VERSION 5.7 ;
  NOWIREEXTENSIONATPIN ON ;
  DIVIDERCHAR "/" ;
  BUSBITCHARS "[]" ;
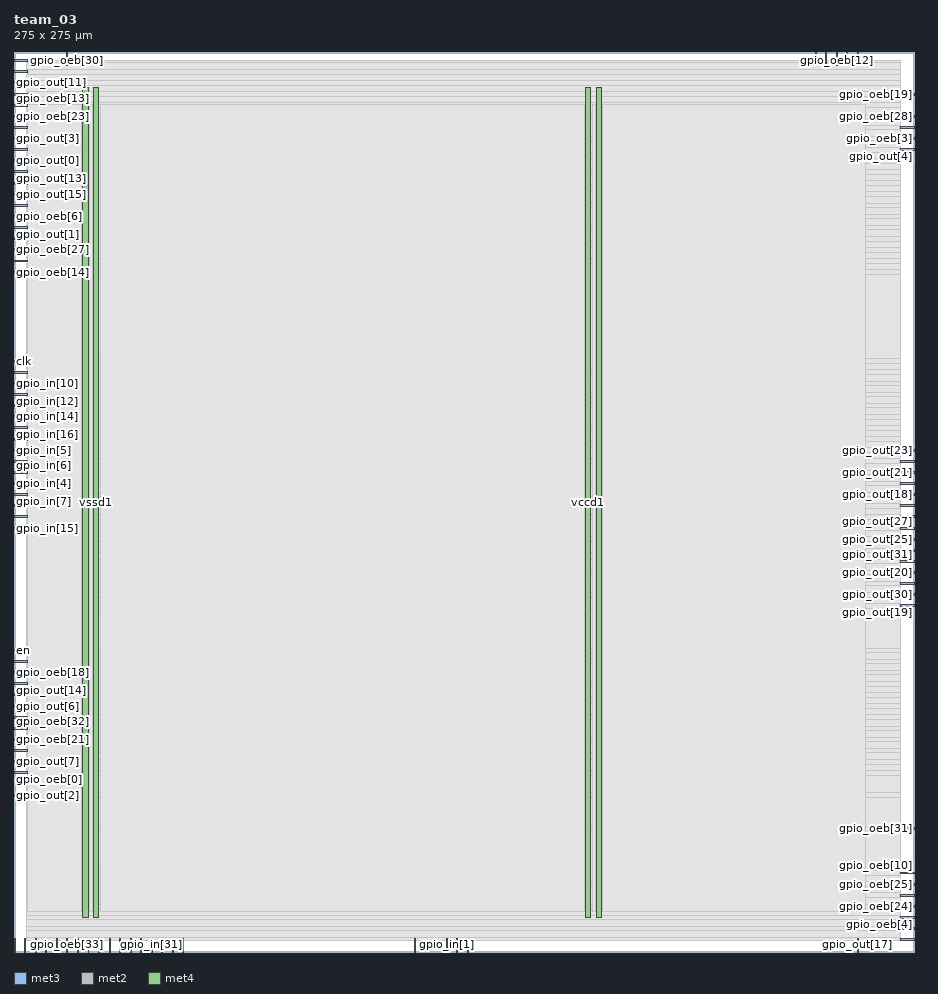
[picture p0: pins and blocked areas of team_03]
MACRO team_03
  CLASS BLOCK ;
  FOREIGN team_03 ;
  ORIGIN 0.000 0.000 ;
  SIZE 275.000 BY 275.000 ;
  PIN clk
    DIRECTION INPUT ;
    USE SIGNAL ;
    ANTENNAGATEAREA 1.286700 ;
    ANTENNADIFFAREA 0.434700 ;
    PORT
      LAYER met3 ;
        RECT 0.000 180.240 4.000 180.840 ;
    END
  END clk
  PIN en
    DIRECTION INPUT ;
    USE SIGNAL ;
    ANTENNAGATEAREA 0.631200 ;
    ANTENNADIFFAREA 0.434700 ;
    PORT
      LAYER met3 ;
        RECT 0.000 91.840 4.000 92.440 ;
    END
  END en
  PIN gpio_in[0]
    DIRECTION INPUT ;
    USE SIGNAL ;
    ANTENNAGATEAREA 0.631200 ;
    ANTENNADIFFAREA 0.434700 ;
    PORT
      LAYER met2 ;
        RECT 135.330 0.000 135.610 4.000 ;
    END
  END gpio_in[0]
  PIN gpio_in[10]
    DIRECTION INPUT ;
    USE SIGNAL ;
    ANTENNAGATEAREA 0.647700 ;
    ANTENNADIFFAREA 0.434700 ;
    PORT
      LAYER met3 ;
        RECT 0.000 173.440 4.000 174.040 ;
    END
  END gpio_in[10]
  PIN gpio_in[11]
    DIRECTION INPUT ;
    USE SIGNAL ;
    ANTENNAGATEAREA 0.593700 ;
    ANTENNADIFFAREA 0.434700 ;
    PORT
      LAYER met3 ;
        RECT 0.000 176.840 4.000 177.440 ;
    END
  END gpio_in[11]
  PIN gpio_in[12]
    DIRECTION INPUT ;
    USE SIGNAL ;
    ANTENNAGATEAREA 0.647700 ;
    ANTENNADIFFAREA 0.434700 ;
    PORT
      LAYER met3 ;
        RECT 0.000 170.040 4.000 170.640 ;
    END
  END gpio_in[12]
  PIN gpio_in[13]
    DIRECTION INPUT ;
    USE SIGNAL ;
    ANTENNAGATEAREA 0.593700 ;
    ANTENNADIFFAREA 0.434700 ;
    PORT
      LAYER met3 ;
        RECT 0.000 166.640 4.000 167.240 ;
    END
  END gpio_in[13]
  PIN gpio_in[14]
    DIRECTION INPUT ;
    USE SIGNAL ;
    ANTENNAGATEAREA 0.647700 ;
    ANTENNADIFFAREA 0.434700 ;
    PORT
      LAYER met3 ;
        RECT 0.000 163.240 4.000 163.840 ;
    END
  END gpio_in[14]
  PIN gpio_in[15]
    DIRECTION INPUT ;
    USE SIGNAL ;
    ANTENNAGATEAREA 0.593700 ;
    ANTENNADIFFAREA 0.434700 ;
    PORT
      LAYER met3 ;
        RECT 0.000 129.240 4.000 129.840 ;
    END
  END gpio_in[15]
  PIN gpio_in[16]
    DIRECTION INPUT ;
    USE SIGNAL ;
    ANTENNAGATEAREA 0.593700 ;
    ANTENNADIFFAREA 0.434700 ;
    PORT
      LAYER met3 ;
        RECT 0.000 159.840 4.000 160.440 ;
    END
  END gpio_in[16]
  PIN gpio_in[17]
    DIRECTION INPUT ;
    USE SIGNAL ;
    ANTENNAGATEAREA 0.593700 ;
    ANTENNADIFFAREA 0.434700 ;
    PORT
      LAYER met3 ;
        RECT 0.000 149.640 4.000 150.240 ;
    END
  END gpio_in[17]
  PIN gpio_in[18]
    DIRECTION INPUT ;
    USE SIGNAL ;
    PORT
      LAYER met2 ;
        RECT 3.310 0.000 3.590 4.000 ;
    END
  END gpio_in[18]
  PIN gpio_in[19]
    DIRECTION INPUT ;
    USE SIGNAL ;
    PORT
      LAYER met2 ;
        RECT 6.530 0.000 6.810 4.000 ;
    END
  END gpio_in[19]
  PIN gpio_in[1]
    DIRECTION INPUT ;
    USE SIGNAL ;
    ANTENNAGATEAREA 0.560700 ;
    ANTENNADIFFAREA 0.434700 ;
    PORT
      LAYER met2 ;
        RECT 132.110 0.000 132.390 4.000 ;
    END
  END gpio_in[1]
  PIN gpio_in[20]
    DIRECTION INPUT ;
    USE SIGNAL ;
    PORT
      LAYER met2 ;
        RECT 9.750 0.000 10.030 4.000 ;
    END
  END gpio_in[20]
  PIN gpio_in[21]
    DIRECTION INPUT ;
    USE SIGNAL ;
    PORT
      LAYER met2 ;
        RECT 12.970 0.000 13.250 4.000 ;
    END
  END gpio_in[21]
  PIN gpio_in[22]
    DIRECTION INPUT ;
    USE SIGNAL ;
    PORT
      LAYER met2 ;
        RECT 19.410 0.000 19.690 4.000 ;
    END
  END gpio_in[22]
  PIN gpio_in[23]
    DIRECTION INPUT ;
    USE SIGNAL ;
    PORT
      LAYER met2 ;
        RECT 0.090 0.000 0.370 4.000 ;
    END
  END gpio_in[23]
  PIN gpio_in[24]
    DIRECTION INPUT ;
    USE SIGNAL ;
    PORT
      LAYER met2 ;
        RECT 25.850 0.000 26.130 4.000 ;
    END
  END gpio_in[24]
  PIN gpio_in[25]
    DIRECTION INPUT ;
    USE SIGNAL ;
    PORT
      LAYER met2 ;
        RECT 22.630 0.000 22.910 4.000 ;
    END
  END gpio_in[25]
  PIN gpio_in[26]
    DIRECTION INPUT ;
    USE SIGNAL ;
    PORT
      LAYER met2 ;
        RECT 32.290 0.000 32.570 4.000 ;
    END
  END gpio_in[26]
  PIN gpio_in[27]
    DIRECTION INPUT ;
    USE SIGNAL ;
    PORT
      LAYER met2 ;
        RECT 29.070 0.000 29.350 4.000 ;
    END
  END gpio_in[27]
  PIN gpio_in[28]
    DIRECTION INPUT ;
    USE SIGNAL ;
    PORT
      LAYER met2 ;
        RECT 38.730 0.000 39.010 4.000 ;
    END
  END gpio_in[28]
  PIN gpio_in[29]
    DIRECTION INPUT ;
    USE SIGNAL ;
    PORT
      LAYER met2 ;
        RECT 35.510 0.000 35.790 4.000 ;
    END
  END gpio_in[29]
  PIN gpio_in[2]
    DIRECTION INPUT ;
    USE SIGNAL ;
    ANTENNAGATEAREA 0.647700 ;
    ANTENNADIFFAREA 0.434700 ;
    PORT
      LAYER met2 ;
        RECT 122.450 0.000 122.730 4.000 ;
    END
  END gpio_in[2]
  PIN gpio_in[30]
    DIRECTION INPUT ;
    USE SIGNAL ;
    PORT
      LAYER met2 ;
        RECT 45.170 0.000 45.450 4.000 ;
    END
  END gpio_in[30]
  PIN gpio_in[31]
    DIRECTION INPUT ;
    USE SIGNAL ;
    PORT
      LAYER met2 ;
        RECT 41.950 0.000 42.230 4.000 ;
    END
  END gpio_in[31]
  PIN gpio_in[32]
    DIRECTION INPUT ;
    USE SIGNAL ;
    PORT
      LAYER met2 ;
        RECT 51.610 0.000 51.890 4.000 ;
    END
  END gpio_in[32]
  PIN gpio_in[33]
    DIRECTION INPUT ;
    USE SIGNAL ;
    PORT
      LAYER met2 ;
        RECT 48.390 0.000 48.670 4.000 ;
    END
  END gpio_in[33]
  PIN gpio_in[3]
    DIRECTION INPUT ;
    USE SIGNAL ;
    ANTENNAGATEAREA 0.647700 ;
    ANTENNADIFFAREA 0.434700 ;
    PORT
      LAYER met3 ;
        RECT 0.000 156.440 4.000 157.040 ;
    END
  END gpio_in[3]
  PIN gpio_in[4]
    DIRECTION INPUT ;
    USE SIGNAL ;
    ANTENNAGATEAREA 0.647700 ;
    ANTENNADIFFAREA 0.434700 ;
    PORT
      LAYER met3 ;
        RECT 0.000 142.840 4.000 143.440 ;
    END
  END gpio_in[4]
  PIN gpio_in[5]
    DIRECTION INPUT ;
    USE SIGNAL ;
    ANTENNAGATEAREA 0.647700 ;
    ANTENNADIFFAREA 0.434700 ;
    PORT
      LAYER met3 ;
        RECT 0.000 153.040 4.000 153.640 ;
    END
  END gpio_in[5]
  PIN gpio_in[6]
    DIRECTION INPUT ;
    USE SIGNAL ;
    ANTENNAGATEAREA 0.647700 ;
    ANTENNADIFFAREA 0.434700 ;
    PORT
      LAYER met3 ;
        RECT 0.000 146.240 4.000 146.840 ;
    END
  END gpio_in[6]
  PIN gpio_in[7]
    DIRECTION INPUT ;
    USE SIGNAL ;
    ANTENNAGATEAREA 0.647700 ;
    ANTENNADIFFAREA 0.434700 ;
    PORT
      LAYER met3 ;
        RECT 0.000 139.440 4.000 140.040 ;
    END
  END gpio_in[7]
  PIN gpio_in[8]
    DIRECTION INPUT ;
    USE SIGNAL ;
    ANTENNAGATEAREA 0.647700 ;
    ANTENNADIFFAREA 0.434700 ;
    PORT
      LAYER met3 ;
        RECT 0.000 136.040 4.000 136.640 ;
    END
  END gpio_in[8]
  PIN gpio_in[9]
    DIRECTION INPUT ;
    USE SIGNAL ;
    ANTENNAGATEAREA 0.647700 ;
    ANTENNADIFFAREA 0.434700 ;
    PORT
      LAYER met3 ;
        RECT 0.000 132.640 4.000 133.240 ;
    END
  END gpio_in[9]
  PIN gpio_oeb[0]
    DIRECTION OUTPUT ;
    USE SIGNAL ;
    PORT
      LAYER met3 ;
        RECT 0.000 54.440 4.000 55.040 ;
    END
  END gpio_oeb[0]
  PIN gpio_oeb[10]
    DIRECTION OUTPUT ;
    USE SIGNAL ;
    PORT
      LAYER met3 ;
        RECT 271.000 23.840 275.000 24.440 ;
    END
  END gpio_oeb[10]
  PIN gpio_oeb[11]
    DIRECTION OUTPUT ;
    USE SIGNAL ;
    PORT
      LAYER met3 ;
        RECT 271.000 251.640 275.000 252.240 ;
    END
  END gpio_oeb[11]
  PIN gpio_oeb[12]
    DIRECTION OUTPUT ;
    USE SIGNAL ;
    PORT
      LAYER met2 ;
        RECT 251.250 271.000 251.530 275.000 ;
    END
  END gpio_oeb[12]
  PIN gpio_oeb[13]
    DIRECTION OUTPUT ;
    USE SIGNAL ;
    PORT
      LAYER met3 ;
        RECT 0.000 258.440 4.000 259.040 ;
    END
  END gpio_oeb[13]
  PIN gpio_oeb[14]
    DIRECTION OUTPUT ;
    USE SIGNAL ;
    PORT
      LAYER met3 ;
        RECT 0.000 207.440 4.000 208.040 ;
    END
  END gpio_oeb[14]
  PIN gpio_oeb[15]
    DIRECTION OUTPUT ;
    USE SIGNAL ;
    PORT
      LAYER met2 ;
        RECT 244.810 271.000 245.090 275.000 ;
    END
  END gpio_oeb[15]
  PIN gpio_oeb[16]
    DIRECTION OUTPUT ;
    USE SIGNAL ;
    PORT
      LAYER met3 ;
        RECT 271.000 3.440 275.000 4.040 ;
    END
  END gpio_oeb[16]
  PIN gpio_oeb[17]
    DIRECTION OUTPUT ;
    USE SIGNAL ;
    PORT
      LAYER met3 ;
        RECT 0.000 272.040 4.000 272.640 ;
    END
  END gpio_oeb[17]
  PIN gpio_oeb[18]
    DIRECTION OUTPUT ;
    USE SIGNAL ;
    PORT
      LAYER met3 ;
        RECT 0.000 85.040 4.000 85.640 ;
    END
  END gpio_oeb[18]
  PIN gpio_oeb[19]
    DIRECTION OUTPUT ;
    USE SIGNAL ;
    PORT
      LAYER met3 ;
        RECT 271.000 261.840 275.000 262.440 ;
    END
  END gpio_oeb[19]
  PIN gpio_oeb[1]
    DIRECTION OUTPUT ;
    USE SIGNAL ;
    PORT
      LAYER met3 ;
        RECT 0.000 61.240 4.000 61.840 ;
    END
  END gpio_oeb[1]
  PIN gpio_oeb[20]
    DIRECTION OUTPUT ;
    USE SIGNAL ;
    PORT
      LAYER met3 ;
        RECT 0.000 71.440 4.000 72.040 ;
    END
  END gpio_oeb[20]
  PIN gpio_oeb[21]
    DIRECTION OUTPUT ;
    USE SIGNAL ;
    PORT
      LAYER met3 ;
        RECT 0.000 64.640 4.000 65.240 ;
    END
  END gpio_oeb[21]
  PIN gpio_oeb[22]
    DIRECTION OUTPUT ;
    USE SIGNAL ;
    PORT
      LAYER met3 ;
        RECT 0.000 251.640 4.000 252.240 ;
    END
  END gpio_oeb[22]
  PIN gpio_oeb[23]
    DIRECTION OUTPUT ;
    USE SIGNAL ;
    PORT
      LAYER met3 ;
        RECT 0.000 255.040 4.000 255.640 ;
    END
  END gpio_oeb[23]
  PIN gpio_oeb[24]
    DIRECTION OUTPUT ;
    USE SIGNAL ;
    PORT
      LAYER met3 ;
        RECT 271.000 13.640 275.000 14.240 ;
    END
  END gpio_oeb[24]
  PIN gpio_oeb[25]
    DIRECTION OUTPUT ;
    USE SIGNAL ;
    PORT
      LAYER met3 ;
        RECT 271.000 20.440 275.000 21.040 ;
    END
  END gpio_oeb[25]
  PIN gpio_oeb[26]
    DIRECTION OUTPUT ;
    USE SIGNAL ;
    PORT
      LAYER met2 ;
        RECT 257.690 271.000 257.970 275.000 ;
    END
  END gpio_oeb[26]
  PIN gpio_oeb[27]
    DIRECTION OUTPUT ;
    USE SIGNAL ;
    PORT
      LAYER met3 ;
        RECT 0.000 214.240 4.000 214.840 ;
    END
  END gpio_oeb[27]
  PIN gpio_oeb[28]
    DIRECTION OUTPUT ;
    USE SIGNAL ;
    PORT
      LAYER met3 ;
        RECT 271.000 255.040 275.000 255.640 ;
    END
  END gpio_oeb[28]
  PIN gpio_oeb[29]
    DIRECTION OUTPUT ;
    USE SIGNAL ;
    PORT
      LAYER met3 ;
        RECT 271.000 17.040 275.000 17.640 ;
    END
  END gpio_oeb[29]
  PIN gpio_oeb[2]
    DIRECTION OUTPUT ;
    USE SIGNAL ;
    PORT
      LAYER met2 ;
        RECT 248.030 271.000 248.310 275.000 ;
    END
  END gpio_oeb[2]
  PIN gpio_oeb[30]
    DIRECTION OUTPUT ;
    USE SIGNAL ;
    PORT
      LAYER met2 ;
        RECT 16.190 271.000 16.470 275.000 ;
    END
  END gpio_oeb[30]
  PIN gpio_oeb[31]
    DIRECTION OUTPUT ;
    USE SIGNAL ;
    PORT
      LAYER met3 ;
        RECT 271.000 37.440 275.000 38.040 ;
    END
  END gpio_oeb[31]
  PIN gpio_oeb[32]
    DIRECTION OUTPUT ;
    USE SIGNAL ;
    PORT
      LAYER met3 ;
        RECT 0.000 68.040 4.000 68.640 ;
    END
  END gpio_oeb[32]
  PIN gpio_oeb[33]
    DIRECTION OUTPUT ;
    USE SIGNAL ;
    PORT
      LAYER met2 ;
        RECT 16.190 0.000 16.470 4.000 ;
    END
  END gpio_oeb[33]
  PIN gpio_oeb[3]
    DIRECTION OUTPUT ;
    USE SIGNAL ;
    PORT
      LAYER met3 ;
        RECT 271.000 248.240 275.000 248.840 ;
    END
  END gpio_oeb[3]
  PIN gpio_oeb[4]
    DIRECTION OUTPUT ;
    USE SIGNAL ;
    PORT
      LAYER met3 ;
        RECT 271.000 10.240 275.000 10.840 ;
    END
  END gpio_oeb[4]
  PIN gpio_oeb[5]
    DIRECTION OUTPUT ;
    USE SIGNAL ;
    PORT
      LAYER met3 ;
        RECT 0.000 88.440 4.000 89.040 ;
    END
  END gpio_oeb[5]
  PIN gpio_oeb[6]
    DIRECTION OUTPUT ;
    USE SIGNAL ;
    PORT
      LAYER met3 ;
        RECT 0.000 224.440 4.000 225.040 ;
    END
  END gpio_oeb[6]
  PIN gpio_oeb[7]
    DIRECTION OUTPUT ;
    USE SIGNAL ;
    PORT
      LAYER met3 ;
        RECT 0.000 217.640 4.000 218.240 ;
    END
  END gpio_oeb[7]
  PIN gpio_oeb[8]
    DIRECTION OUTPUT ;
    USE SIGNAL ;
    PORT
      LAYER met3 ;
        RECT 0.000 210.840 4.000 211.440 ;
    END
  END gpio_oeb[8]
  PIN gpio_oeb[9]
    DIRECTION OUTPUT ;
    USE SIGNAL ;
    PORT
      LAYER met3 ;
        RECT 0.000 234.640 4.000 235.240 ;
    END
  END gpio_oeb[9]
  PIN gpio_out[0]
    DIRECTION OUTPUT ;
    USE SIGNAL ;
    PORT
      LAYER met3 ;
        RECT 0.000 241.440 4.000 242.040 ;
    END
  END gpio_out[0]
  PIN gpio_out[10]
    DIRECTION OUTPUT ;
    USE SIGNAL ;
    PORT
      LAYER met3 ;
        RECT 0.000 268.640 4.000 269.240 ;
    END
  END gpio_out[10]
  PIN gpio_out[11]
    DIRECTION OUTPUT ;
    USE SIGNAL ;
    PORT
      LAYER met3 ;
        RECT 0.000 265.240 4.000 265.840 ;
    END
  END gpio_out[11]
  PIN gpio_out[12]
    DIRECTION OUTPUT ;
    USE SIGNAL ;
    PORT
      LAYER met2 ;
        RECT 254.470 271.000 254.750 275.000 ;
    END
  END gpio_out[12]
  PIN gpio_out[13]
    DIRECTION OUTPUT ;
    USE SIGNAL ;
    PORT
      LAYER met3 ;
        RECT 0.000 238.040 4.000 238.640 ;
    END
  END gpio_out[13]
  PIN gpio_out[14]
    DIRECTION OUTPUT ;
    USE SIGNAL ;
    PORT
      LAYER met3 ;
        RECT 0.000 81.640 4.000 82.240 ;
    END
  END gpio_out[14]
  PIN gpio_out[15]
    DIRECTION OUTPUT ;
    USE SIGNAL ;
    PORT
      LAYER met3 ;
        RECT 0.000 231.240 4.000 231.840 ;
    END
  END gpio_out[15]
  PIN gpio_out[16]
    DIRECTION OUTPUT ;
    USE SIGNAL ;
    PORT
      LAYER met3 ;
        RECT 0.000 261.840 4.000 262.440 ;
    END
  END gpio_out[16]
  PIN gpio_out[17]
    DIRECTION OUTPUT ;
    USE SIGNAL ;
    PORT
      LAYER met2 ;
        RECT 257.690 0.000 257.970 4.000 ;
    END
  END gpio_out[17]
  PIN gpio_out[18]
    DIRECTION OUTPUT ;
    USE SIGNAL ;
    ANTENNADIFFAREA 0.445500 ;
    PORT
      LAYER met3 ;
        RECT 271.000 139.440 275.000 140.040 ;
    END
  END gpio_out[18]
  PIN gpio_out[19]
    DIRECTION OUTPUT ;
    USE SIGNAL ;
    ANTENNADIFFAREA 0.445500 ;
    PORT
      LAYER met3 ;
        RECT 271.000 105.440 275.000 106.040 ;
    END
  END gpio_out[19]
  PIN gpio_out[1]
    DIRECTION OUTPUT ;
    USE SIGNAL ;
    PORT
      LAYER met3 ;
        RECT 0.000 221.040 4.000 221.640 ;
    END
  END gpio_out[1]
  PIN gpio_out[20]
    DIRECTION OUTPUT ;
    USE SIGNAL ;
    ANTENNADIFFAREA 0.445500 ;
    PORT
      LAYER met3 ;
        RECT 271.000 115.640 275.000 116.240 ;
    END
  END gpio_out[20]
  PIN gpio_out[21]
    DIRECTION OUTPUT ;
    USE SIGNAL ;
    ANTENNADIFFAREA 0.445500 ;
    PORT
      LAYER met3 ;
        RECT 271.000 146.240 275.000 146.840 ;
    END
  END gpio_out[21]
  PIN gpio_out[22]
    DIRECTION OUTPUT ;
    USE SIGNAL ;
    ANTENNADIFFAREA 0.445500 ;
    PORT
      LAYER met3 ;
        RECT 271.000 149.640 275.000 150.240 ;
    END
  END gpio_out[22]
  PIN gpio_out[23]
    DIRECTION OUTPUT ;
    USE SIGNAL ;
    ANTENNADIFFAREA 0.445500 ;
    PORT
      LAYER met3 ;
        RECT 271.000 153.040 275.000 153.640 ;
    END
  END gpio_out[23]
  PIN gpio_out[24]
    DIRECTION OUTPUT ;
    USE SIGNAL ;
    ANTENNADIFFAREA 0.445500 ;
    PORT
      LAYER met3 ;
        RECT 271.000 142.840 275.000 143.440 ;
    END
  END gpio_out[24]
  PIN gpio_out[25]
    DIRECTION OUTPUT ;
    USE SIGNAL ;
    ANTENNADIFFAREA 0.445500 ;
    PORT
      LAYER met3 ;
        RECT 271.000 125.840 275.000 126.440 ;
    END
  END gpio_out[25]
  PIN gpio_out[26]
    DIRECTION OUTPUT ;
    USE SIGNAL ;
    ANTENNADIFFAREA 0.445500 ;
    PORT
      LAYER met3 ;
        RECT 271.000 122.440 275.000 123.040 ;
    END
  END gpio_out[26]
  PIN gpio_out[27]
    DIRECTION OUTPUT ;
    USE SIGNAL ;
    ANTENNADIFFAREA 0.445500 ;
    PORT
      LAYER met3 ;
        RECT 271.000 129.240 275.000 129.840 ;
    END
  END gpio_out[27]
  PIN gpio_out[28]
    DIRECTION OUTPUT ;
    USE SIGNAL ;
    ANTENNADIFFAREA 0.445500 ;
    PORT
      LAYER met3 ;
        RECT 271.000 136.040 275.000 136.640 ;
    END
  END gpio_out[28]
  PIN gpio_out[29]
    DIRECTION OUTPUT ;
    USE SIGNAL ;
    ANTENNADIFFAREA 0.445500 ;
    PORT
      LAYER met3 ;
        RECT 271.000 132.640 275.000 133.240 ;
    END
  END gpio_out[29]
  PIN gpio_out[2]
    DIRECTION OUTPUT ;
    USE SIGNAL ;
    PORT
      LAYER met3 ;
        RECT 0.000 47.640 4.000 48.240 ;
    END
  END gpio_out[2]
  PIN gpio_out[30]
    DIRECTION OUTPUT ;
    USE SIGNAL ;
    ANTENNADIFFAREA 0.445500 ;
    PORT
      LAYER met3 ;
        RECT 271.000 108.840 275.000 109.440 ;
    END
  END gpio_out[30]
  PIN gpio_out[31]
    DIRECTION OUTPUT ;
    USE SIGNAL ;
    ANTENNADIFFAREA 0.445500 ;
    PORT
      LAYER met3 ;
        RECT 271.000 119.040 275.000 119.640 ;
    END
  END gpio_out[31]
  PIN gpio_out[32]
    DIRECTION OUTPUT ;
    USE SIGNAL ;
    ANTENNADIFFAREA 0.445500 ;
    PORT
      LAYER met3 ;
        RECT 271.000 112.240 275.000 112.840 ;
    END
  END gpio_out[32]
  PIN gpio_out[33]
    DIRECTION OUTPUT ;
    USE SIGNAL ;
    ANTENNADIFFAREA 0.445500 ;
    PORT
      LAYER met2 ;
        RECT 138.550 0.000 138.830 4.000 ;
    END
  END gpio_out[33]
  PIN gpio_out[3]
    DIRECTION OUTPUT ;
    USE SIGNAL ;
    PORT
      LAYER met3 ;
        RECT 0.000 248.240 4.000 248.840 ;
    END
  END gpio_out[3]
  PIN gpio_out[4]
    DIRECTION OUTPUT ;
    USE SIGNAL ;
    PORT
      LAYER met3 ;
        RECT 271.000 244.840 275.000 245.440 ;
    END
  END gpio_out[4]
  PIN gpio_out[5]
    DIRECTION OUTPUT ;
    USE SIGNAL ;
    PORT
      LAYER met3 ;
        RECT 0.000 244.840 4.000 245.440 ;
    END
  END gpio_out[5]
  PIN gpio_out[6]
    DIRECTION OUTPUT ;
    USE SIGNAL ;
    PORT
      LAYER met3 ;
        RECT 0.000 74.840 4.000 75.440 ;
    END
  END gpio_out[6]
  PIN gpio_out[7]
    DIRECTION OUTPUT ;
    USE SIGNAL ;
    PORT
      LAYER met3 ;
        RECT 0.000 57.840 4.000 58.440 ;
    END
  END gpio_out[7]
  PIN gpio_out[8]
    DIRECTION OUTPUT ;
    USE SIGNAL ;
    PORT
      LAYER met3 ;
        RECT 271.000 6.840 275.000 7.440 ;
    END
  END gpio_out[8]
  PIN gpio_out[9]
    DIRECTION OUTPUT ;
    USE SIGNAL ;
    PORT
      LAYER met3 ;
        RECT 0.000 227.840 4.000 228.440 ;
    END
  END gpio_out[9]
  PIN nrst
    DIRECTION INPUT ;
    USE SIGNAL ;
    ANTENNAGATEAREA 0.631200 ;
    ANTENNADIFFAREA 0.434700 ;
    PORT
      LAYER met3 ;
        RECT 0.000 78.240 4.000 78.840 ;
    END
  END nrst
  PIN vccd1
    DIRECTION INOUT ;
    USE POWER ;
    PORT
      LAYER met4 ;
        RECT 21.040 10.640 22.640 264.080 ;
    END
    PORT
      LAYER met4 ;
        RECT 174.640 10.640 176.240 264.080 ;
    END
  END vccd1
  PIN vssd1
    DIRECTION INOUT ;
    USE GROUND ;
    PORT
      LAYER met4 ;
        RECT 24.340 10.640 25.940 264.080 ;
    END
    PORT
      LAYER met4 ;
        RECT 177.940 10.640 179.540 264.080 ;
    END
  END vssd1
  OBS
      LAYER nwell ;
        RECT 5.330 10.760 269.290 264.030 ;
      LAYER li1 ;
        RECT 5.520 10.795 269.100 263.925 ;
      LAYER met1 ;
        RECT 4.210 9.900 269.100 264.080 ;
      LAYER met2 ;
        RECT 4.230 270.720 15.910 272.525 ;
        RECT 16.750 270.720 244.530 272.525 ;
        RECT 245.370 270.720 247.750 272.525 ;
        RECT 248.590 270.720 250.970 272.525 ;
        RECT 251.810 270.720 254.190 272.525 ;
        RECT 255.030 270.720 257.410 272.525 ;
        RECT 258.250 270.720 268.540 272.525 ;
        RECT 4.230 4.280 268.540 270.720 ;
        RECT 4.230 3.555 6.250 4.280 ;
        RECT 7.090 3.555 9.470 4.280 ;
        RECT 10.310 3.555 12.690 4.280 ;
        RECT 13.530 3.555 15.910 4.280 ;
        RECT 16.750 3.555 19.130 4.280 ;
        RECT 19.970 3.555 22.350 4.280 ;
        RECT 23.190 3.555 25.570 4.280 ;
        RECT 26.410 3.555 28.790 4.280 ;
        RECT 29.630 3.555 32.010 4.280 ;
        RECT 32.850 3.555 35.230 4.280 ;
        RECT 36.070 3.555 38.450 4.280 ;
        RECT 39.290 3.555 41.670 4.280 ;
        RECT 42.510 3.555 44.890 4.280 ;
        RECT 45.730 3.555 48.110 4.280 ;
        RECT 48.950 3.555 51.330 4.280 ;
        RECT 52.170 3.555 122.170 4.280 ;
        RECT 123.010 3.555 131.830 4.280 ;
        RECT 132.670 3.555 135.050 4.280 ;
        RECT 135.890 3.555 138.270 4.280 ;
        RECT 139.110 3.555 257.410 4.280 ;
        RECT 258.250 3.555 268.540 4.280 ;
      LAYER met3 ;
        RECT 4.400 271.640 271.000 272.505 ;
        RECT 3.950 269.640 271.000 271.640 ;
        RECT 4.400 268.240 271.000 269.640 ;
        RECT 3.950 266.240 271.000 268.240 ;
        RECT 4.400 264.840 271.000 266.240 ;
        RECT 3.950 262.840 271.000 264.840 ;
        RECT 4.400 261.440 270.600 262.840 ;
        RECT 3.950 259.440 271.000 261.440 ;
        RECT 4.400 258.040 271.000 259.440 ;
        RECT 3.950 256.040 271.000 258.040 ;
        RECT 4.400 254.640 270.600 256.040 ;
        RECT 3.950 252.640 271.000 254.640 ;
        RECT 4.400 251.240 270.600 252.640 ;
        RECT 3.950 249.240 271.000 251.240 ;
        RECT 4.400 247.840 270.600 249.240 ;
        RECT 3.950 245.840 271.000 247.840 ;
        RECT 4.400 244.440 270.600 245.840 ;
        RECT 3.950 242.440 271.000 244.440 ;
        RECT 4.400 241.040 271.000 242.440 ;
        RECT 3.950 239.040 271.000 241.040 ;
        RECT 4.400 237.640 271.000 239.040 ;
        RECT 3.950 235.640 271.000 237.640 ;
        RECT 4.400 234.240 271.000 235.640 ;
        RECT 3.950 232.240 271.000 234.240 ;
        RECT 4.400 230.840 271.000 232.240 ;
        RECT 3.950 228.840 271.000 230.840 ;
        RECT 4.400 227.440 271.000 228.840 ;
        RECT 3.950 225.440 271.000 227.440 ;
        RECT 4.400 224.040 271.000 225.440 ;
        RECT 3.950 222.040 271.000 224.040 ;
        RECT 4.400 220.640 271.000 222.040 ;
        RECT 3.950 218.640 271.000 220.640 ;
        RECT 4.400 217.240 271.000 218.640 ;
        RECT 3.950 215.240 271.000 217.240 ;
        RECT 4.400 213.840 271.000 215.240 ;
        RECT 3.950 211.840 271.000 213.840 ;
        RECT 4.400 210.440 271.000 211.840 ;
        RECT 3.950 208.440 271.000 210.440 ;
        RECT 4.400 207.040 271.000 208.440 ;
        RECT 3.950 181.240 271.000 207.040 ;
        RECT 4.400 179.840 271.000 181.240 ;
        RECT 3.950 177.840 271.000 179.840 ;
        RECT 4.400 176.440 271.000 177.840 ;
        RECT 3.950 174.440 271.000 176.440 ;
        RECT 4.400 173.040 271.000 174.440 ;
        RECT 3.950 171.040 271.000 173.040 ;
        RECT 4.400 169.640 271.000 171.040 ;
        RECT 3.950 167.640 271.000 169.640 ;
        RECT 4.400 166.240 271.000 167.640 ;
        RECT 3.950 164.240 271.000 166.240 ;
        RECT 4.400 162.840 271.000 164.240 ;
        RECT 3.950 160.840 271.000 162.840 ;
        RECT 4.400 159.440 271.000 160.840 ;
        RECT 3.950 157.440 271.000 159.440 ;
        RECT 4.400 156.040 271.000 157.440 ;
        RECT 3.950 154.040 271.000 156.040 ;
        RECT 4.400 152.640 270.600 154.040 ;
        RECT 3.950 150.640 271.000 152.640 ;
        RECT 4.400 149.240 270.600 150.640 ;
        RECT 3.950 147.240 271.000 149.240 ;
        RECT 4.400 145.840 270.600 147.240 ;
        RECT 3.950 143.840 271.000 145.840 ;
        RECT 4.400 142.440 270.600 143.840 ;
        RECT 3.950 140.440 271.000 142.440 ;
        RECT 4.400 139.040 270.600 140.440 ;
        RECT 3.950 137.040 271.000 139.040 ;
        RECT 4.400 135.640 270.600 137.040 ;
        RECT 3.950 133.640 271.000 135.640 ;
        RECT 4.400 132.240 270.600 133.640 ;
        RECT 3.950 130.240 271.000 132.240 ;
        RECT 4.400 128.840 270.600 130.240 ;
        RECT 3.950 126.840 271.000 128.840 ;
        RECT 3.950 125.440 270.600 126.840 ;
        RECT 3.950 123.440 271.000 125.440 ;
        RECT 3.950 122.040 270.600 123.440 ;
        RECT 3.950 120.040 271.000 122.040 ;
        RECT 3.950 118.640 270.600 120.040 ;
        RECT 3.950 116.640 271.000 118.640 ;
        RECT 3.950 115.240 270.600 116.640 ;
        RECT 3.950 113.240 271.000 115.240 ;
        RECT 3.950 111.840 270.600 113.240 ;
        RECT 3.950 109.840 271.000 111.840 ;
        RECT 3.950 108.440 270.600 109.840 ;
        RECT 3.950 106.440 271.000 108.440 ;
        RECT 3.950 105.040 270.600 106.440 ;
        RECT 3.950 92.840 271.000 105.040 ;
        RECT 4.400 91.440 271.000 92.840 ;
        RECT 3.950 89.440 271.000 91.440 ;
        RECT 4.400 88.040 271.000 89.440 ;
        RECT 3.950 86.040 271.000 88.040 ;
        RECT 4.400 84.640 271.000 86.040 ;
        RECT 3.950 82.640 271.000 84.640 ;
        RECT 4.400 81.240 271.000 82.640 ;
        RECT 3.950 79.240 271.000 81.240 ;
        RECT 4.400 77.840 271.000 79.240 ;
        RECT 3.950 75.840 271.000 77.840 ;
        RECT 4.400 74.440 271.000 75.840 ;
        RECT 3.950 72.440 271.000 74.440 ;
        RECT 4.400 71.040 271.000 72.440 ;
        RECT 3.950 69.040 271.000 71.040 ;
        RECT 4.400 67.640 271.000 69.040 ;
        RECT 3.950 65.640 271.000 67.640 ;
        RECT 4.400 64.240 271.000 65.640 ;
        RECT 3.950 62.240 271.000 64.240 ;
        RECT 4.400 60.840 271.000 62.240 ;
        RECT 3.950 58.840 271.000 60.840 ;
        RECT 4.400 57.440 271.000 58.840 ;
        RECT 3.950 55.440 271.000 57.440 ;
        RECT 4.400 54.040 271.000 55.440 ;
        RECT 3.950 48.640 271.000 54.040 ;
        RECT 4.400 47.240 271.000 48.640 ;
        RECT 3.950 38.440 271.000 47.240 ;
        RECT 3.950 37.040 270.600 38.440 ;
        RECT 3.950 24.840 271.000 37.040 ;
        RECT 3.950 23.440 270.600 24.840 ;
        RECT 3.950 21.440 271.000 23.440 ;
        RECT 3.950 20.040 270.600 21.440 ;
        RECT 3.950 18.040 271.000 20.040 ;
        RECT 3.950 16.640 270.600 18.040 ;
        RECT 3.950 14.640 271.000 16.640 ;
        RECT 3.950 13.240 270.600 14.640 ;
        RECT 3.950 11.240 271.000 13.240 ;
        RECT 3.950 9.840 270.600 11.240 ;
        RECT 3.950 7.840 271.000 9.840 ;
        RECT 3.950 6.440 270.600 7.840 ;
        RECT 3.950 4.440 271.000 6.440 ;
        RECT 3.950 3.575 270.600 4.440 ;
      LAYER met4 ;
        RECT 3.975 12.415 20.640 258.905 ;
        RECT 23.040 12.415 23.940 258.905 ;
        RECT 26.340 12.415 174.240 258.905 ;
        RECT 176.640 12.415 177.540 258.905 ;
        RECT 179.940 12.415 260.065 258.905 ;
  END
END team_03
END LIBRARY

